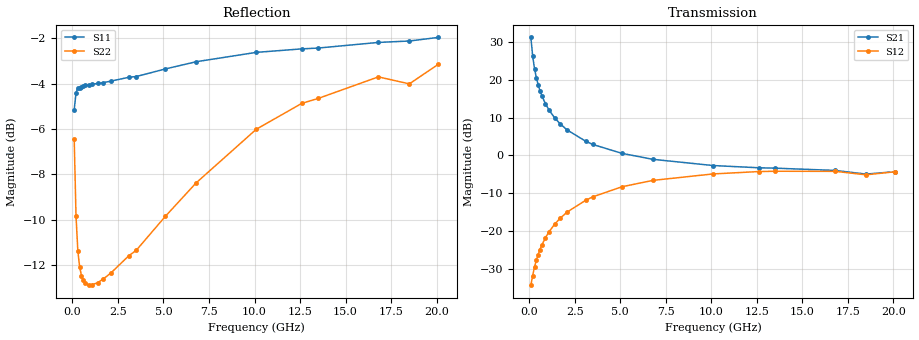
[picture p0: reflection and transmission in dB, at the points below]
!  Infineon Technologies AG
! BFR380L3 , PF131585-7, No.6, Th 09.10.01, soldered on pcb-board, measured with PP GSG850
!  Vce=1.0 V,  Ic=60.0 mA
! Common Emitter S-Parameters:  15. November 2001
#  GHz  S  MA  R  50
! f  S11  S21  S12  S22
! GHz  Mag  Ang  Mag  Ang  Mag  Ang  Mag  Ang
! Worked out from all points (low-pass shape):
!   201 points, 100 MHz to 20.1 GHz, reference 50 ohm
!   highest |S21| = 31.22 dB at 100 MHz (marker M1); lowest = -5.0 dB at 18.5 GHz (marker M2)
!   |S21| within 3 dB of the highest: start of sweep to 160.1 MHz
!   lowest |S11| = -5.2 dB at 100 MHz (marker M3), VSWR 3.47, Z = 17.2 - j20.7 ohm
!   |S11| at or under -10 dB: nowhere
!   |S22| runs from -12.9 to -3.1 dB; largest |S21 - S12| = 36
!   S11 on the Smith chart (normalised r, x): 100 MHz: 0.34, -0.41; 600 MHz: 0.23, -0.01; 3.1 GHz: 0.24, +0.36; 6.8 GHz: 0.30, +0.83; 12.6 GHz: 0.51, +1.56; 20.1 GHz: 0.99, +2.62
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0.1  0.5524 -130.6  36.4 120.8  0.01915 53.6  0.4755 -80.5
0.2  0.6023 -156.4  20.5 104.3  0.02563 57.0  0.3222 -112.6
0.3  0.6167 -166.0  14.05 97.3  0.03326 61.2  0.27 -130.0
0.4  0.6184 -172.1  10.64 92.8  0.04067 64.3  0.2489 -141.0
0.5  0.6216 -176.1  8.569 89.5  0.04862 67.1  0.2384 -148.6
0.6  0.6224 -179.4  7.167 86.8  0.05668 68.2  0.2327 -154.0
0.7  0.625 177.9  6.166 84.4  0.06481 69.1  0.2299 -158.3
0.9  0.6263 173.2  4.821 80.2  0.0812 69.7  0.2272 -164.4
1.1  0.629 169.2  3.974 76.4  0.0977 69.6  0.2278 -168.7
1.4  0.6313 163.9  3.151 71.2  0.1221 68.6  0.2301 -173.5
1.7  0.6338 159.0  2.621 66.3  0.1464 67.0  0.2345 -177.3
2.1  0.6387 152.8  2.16 60.2  0.1781 64.4  0.2413 178.5
3.1  0.6514 138.6  1.542 46.5  0.2532 57.0  0.2637 169.2
3.5  0.6537 133.2  1.393 41.4  0.2822 53.8  0.2708 166.0
5.1  0.6794 114.7  1.062 24.3  0.3836 41.0  0.3218 152.1
6.8  0.7048 97.9  0.8854 10.5  0.466 28.4  0.3816 136.9
10.1  0.739 74.2  0.7329 -8.4  0.5672 6.7  0.5006 112.4
12.6  0.7522 61.5  0.6848 -19.4  0.6095 -8.0  0.5708 94.6
13.5  0.7554 57.6  0.6765 -23.4  0.6157 -13.0  0.5852 89.4
16.8  0.7772 46.3  0.6316 -34.1  0.6142 -27.8  0.6527 71.2
18.5  0.7828 44.3  0.5647 -41.5  0.5525 -35.9  0.63 66.8
20.1  0.7973 37.4  0.6077 -44.7  0.6063 -40.6  0.6959 56.8
